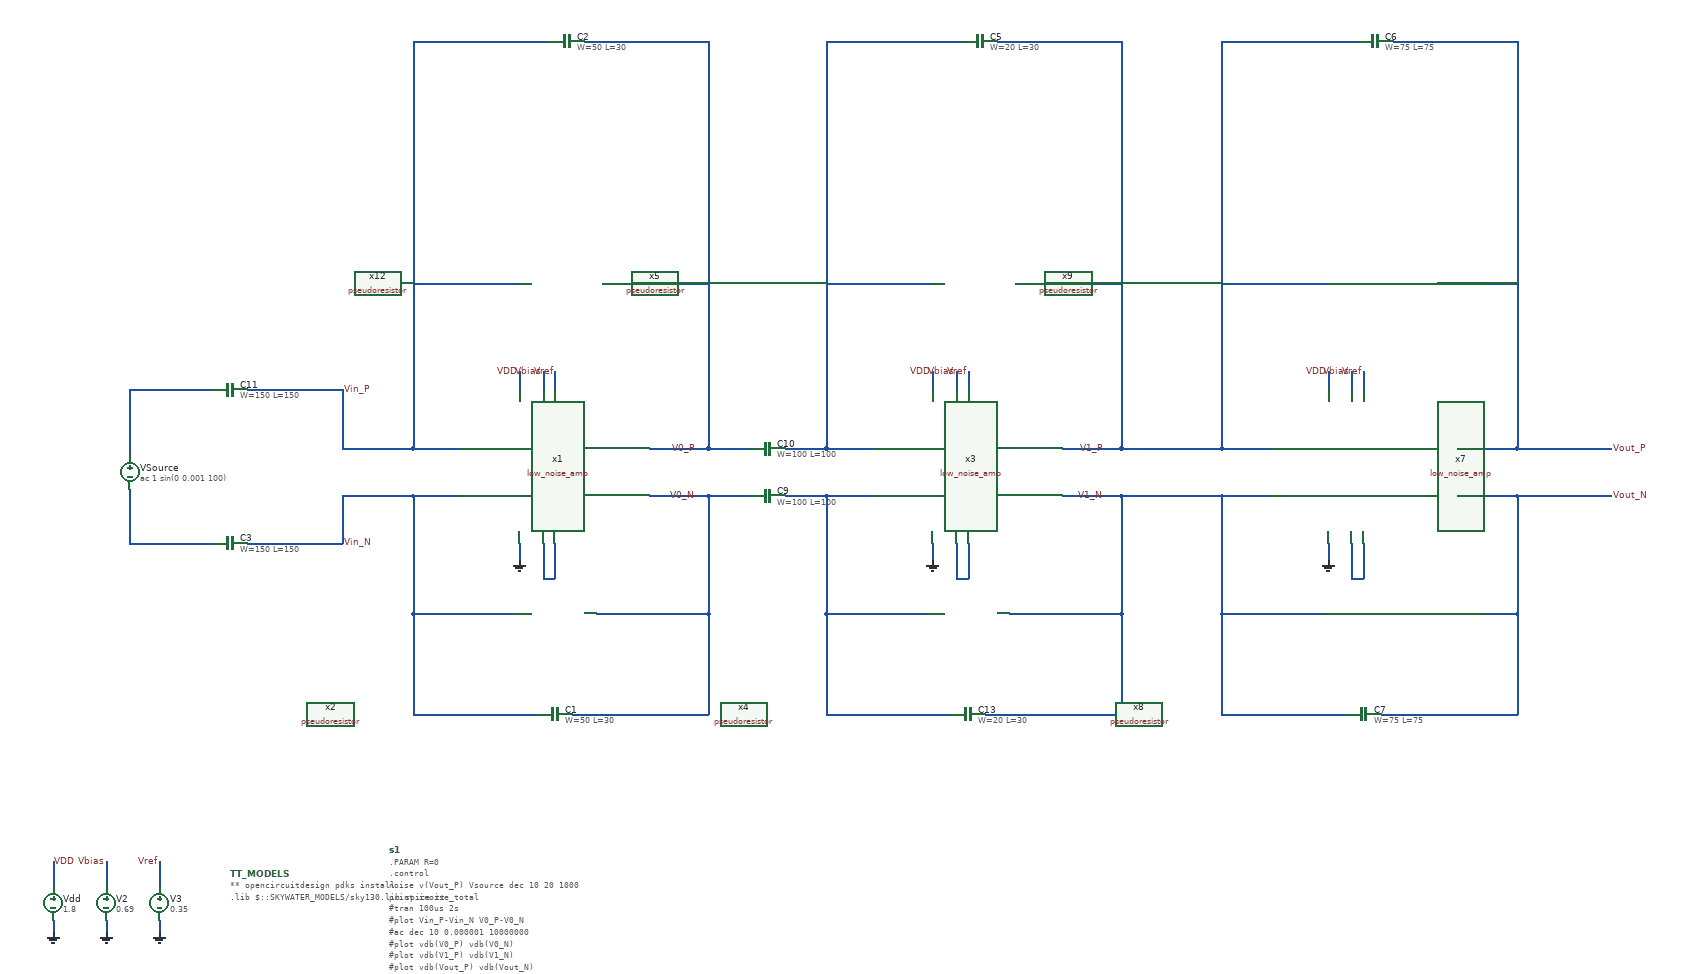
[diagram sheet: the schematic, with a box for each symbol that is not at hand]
v {xschem version=3.4.5 file_version=1.2
}
G {}
K {}
V {}
S {}
E {}
N 710 -910 790 -910 {
lab=Vin_P}
N 1210 -1130 1210 -910 {
lab=V0_P}
N 710 -1130 710 -910 {
lab=Vin_P}
N 710 -830 790 -830 {
lab=Vin_N}
N 1210 -830 1210 -630 {
lab=V0_N}
N 710 -1600 710 -1480 {
lab=Vin_P}
N 710 -1600 940 -1600 {
lab=Vin_P}
N 1210 -1600 1210 -1480 {
lab=V0_P}
N 710 -830 710 -630 {
lab=Vin_N}
N 710 -630 880 -630 {
lab=Vin_N}
N 590 -1010 590 -910 {
lab=Vin_P}
N 590 -830 590 -750 {
lab=Vin_N}
N 930 -750 930 -690 {
lab=#net1}
N 930 -690 950 -690 {
lab=#net1}
N 950 -750 950 -690 {
lab=#net1}
N 890 -1040 890 -1010 {
lab=VDD}
N 930 -1040 930 -1010 {
lab=Vbias}
N 950 -1040 950 -1010 {
lab=Vref}
N 890 -750 890 -720 {
lab=GND}
N 100 -110 100 -90 {
lab=GND}
N 100 -210 100 -170 {
lab=VDD}
N 1020 -630 1210 -630 {
lab=V0_N}
N 230 -1010 230 -900 {
lab=#net2}
N 230 -840 230 -750 {
lab=#net3}
N 1000 -1600 1210 -1600 {
lab=V0_P}
N 190 -110 190 -90 {
lab=GND}
N 190 -210 190 -170 {
lab=Vbias}
N 280 -210 280 -170 {
lab=Vref}
N 280 -110 280 -90 {
lab=GND}
N 1110 -910 1210 -910 {
lab=V0_P}
N 590 -910 710 -910 {
lab=Vin_P}
N 1110 -830 1210 -830 {
lab=V0_N}
N 590 -830 710 -830 {
lab=Vin_N}
N 710 -460 920 -460 {
lab=Vin_N}
N 980 -460 1210 -460 {
lab=V0_N}
N 710 -1480 710 -1130 {
lab=Vin_P}
N 1210 -1480 1210 -1130 {
lab=V0_P}
N 710 -620 710 -460 {
lab=Vin_N}
N 710 -630 710 -620 {
lab=Vin_N}
N 1210 -630 1210 -460 {
lab=V0_N}
N 1410 -910 1490 -910 {
lab=#net4}
N 1910 -1130 1910 -910 {
lab=V1_P}
N 1410 -1130 1410 -910 {
lab=#net4}
N 1410 -830 1490 -830 {
lab=#net5}
N 1910 -830 1910 -630 {
lab=V1_N}
N 1410 -1600 1410 -1480 {
lab=#net4}
N 1410 -1600 1640 -1600 {
lab=#net4}
N 1910 -1600 1910 -1480 {
lab=V1_P}
N 1410 -830 1410 -630 {
lab=#net5}
N 1410 -630 1580 -630 {
lab=#net5}
N 1630 -750 1630 -690 {
lab=#net6}
N 1630 -690 1650 -690 {
lab=#net6}
N 1650 -750 1650 -690 {
lab=#net6}
N 1590 -1040 1590 -1010 {
lab=VDD}
N 1630 -1040 1630 -1010 {
lab=Vbias}
N 1650 -1040 1650 -1010 {
lab=Vref}
N 1590 -750 1590 -720 {
lab=GND}
N 1720 -630 1910 -630 {
lab=V1_N}
N 1700 -1600 1910 -1600 {
lab=V1_P}
N 1810 -910 1910 -910 {
lab=V1_P}
N 1810 -830 1910 -830 {
lab=V1_N}
N 1410 -460 1620 -460 {
lab=#net5}
N 1680 -460 1910 -460 {
lab=V1_N}
N 1410 -1480 1410 -1130 {
lab=#net4}
N 1910 -1480 1910 -1130 {
lab=V1_P}
N 1410 -1190 1590 -1190 {
lab=#net4}
N 1730 -1190 1910 -1190 {
lab=V1_P}
N 1410 -620 1410 -460 {
lab=#net5}
N 1410 -630 1410 -620 {
lab=#net5}
N 1910 -630 1910 -460 {
lab=V1_N}
N 2080 -910 2160 -910 {
lab=#net7}
N 2580 -1130 2580 -910 {
lab=Vout_P}
N 2080 -1130 2080 -910 {
lab=#net7}
N 2080 -830 2160 -830 {
lab=#net8}
N 2580 -830 2580 -630 {
lab=Vout_N}
N 2080 -1600 2080 -1480 {
lab=#net7}
N 2080 -1600 2310 -1600 {
lab=#net7}
N 2580 -1600 2580 -1480 {
lab=Vout_P}
N 2080 -830 2080 -630 {
lab=#net8}
N 2080 -630 2250 -630 {
lab=#net8}
N 2300 -750 2300 -690 {
lab=#net9}
N 2300 -690 2320 -690 {
lab=#net9}
N 2320 -750 2320 -690 {
lab=#net9}
N 2260 -1040 2260 -1010 {
lab=VDD}
N 2300 -1040 2300 -1010 {
lab=Vbias}
N 2320 -1040 2320 -1010 {
lab=Vref}
N 2260 -750 2260 -720 {
lab=GND}
N 2390 -630 2580 -630 {
lab=Vout_N}
N 2370 -1600 2580 -1600 {
lab=Vout_P}
N 2480 -910 2580 -910 {
lab=Vout_P}
N 2480 -830 2580 -830 {
lab=Vout_N}
N 2080 -460 2290 -460 {
lab=#net8}
N 2350 -460 2580 -460 {
lab=Vout_N}
N 2080 -1480 2080 -1130 {
lab=#net7}
N 2580 -1480 2580 -1130 {
lab=Vout_P}
N 2080 -1190 2260 -1190 {
lab=#net7}
N 2400 -1190 2580 -1190 {
lab=Vout_P}
N 2080 -620 2080 -460 {
lab=#net8}
N 2080 -630 2080 -620 {
lab=#net8}
N 2580 -630 2580 -460 {
lab=Vout_N}
N 2580 -830 2740 -830 {
lab=Vout_N}
N 2580 -910 2740 -910 {
lab=Vout_P}
N 710 -1190 890 -1190 {
lab=Vin_P}
N 1030 -1190 1210 -1190 {
lab=V0_P}
N 1340 -830 1410 -830 {
lab=#net5}
N 1340 -910 1410 -910 {
lab=#net4}
N 1210 -830 1280 -830 {
lab=V0_N}
N 1210 -910 1280 -910 {
lab=V0_P}
N 1910 -910 1960 -910 {
lab=V1_P}
N 1910 -830 1960 -830 {
lab=V1_N}
N 2020 -910 2080 -910 {
lab=#net7}
N 2020 -830 2080 -830 {
lab=#net8}
N 230 -750 270 -750 {
lab=#net3}
N 330 -750 370 -750 {
lab=#net3}
N 230 -1010 260 -1010 {
lab=#net2}
N 320 -1010 370 -1010 {
lab=#net2}
N 430 -1010 590 -1010 {
lab=Vin_P}
N 430 -750 590 -750 {
lab=Vin_N}
N 260 -1010 310 -1010 {
lab=#net2}
N 310 -1010 320 -1010 {
lab=#net2}
N 270 -750 330 -750 {
lab=#net3}
N 1960 -910 2020 -910 {}
N 1960 -830 2020 -830 {}
C {low_noise_amp.sym} 950 -870 0 0 {name=x1}
C {devices/lab_pin.sym} 890 -1040 1 0 {name=p1 sig_type=std_logic lab=VDD}
C {devices/lab_pin.sym} 930 -1040 1 0 {name=p2 sig_type=std_logic lab=Vbias}
C {devices/lab_pin.sym} 950 -1040 1 0 {name=p3 sig_type=std_logic lab=Vref}
C {devices/vsource.sym} 100 -140 0 0 {name=Vdd value=1.8 savecurrent=false}
C {devices/vsource.sym} 190 -140 0 0 {name=V2 value=0.69 savecurrent=false}
C {devices/vsource.sym} 280 -140 0 0 {name=V3 value=0.35 savecurrent=false}
C {devices/gnd.sym} 100 -90 0 0 {name=l1 lab=GND}
C {devices/lab_pin.sym} 100 -210 0 1 {name=p5 sig_type=std_logic lab=VDD}
C {devices/vsource.sym} 230 -870 0 0 {name=VSource value="ac 1 sin(0 0.001 100)" savecurrent=false
#sin(0 0.001 1)
}
C {devices/lab_pin.sym} 590 -1010 0 1 {name=p8 sig_type=std_logic lab=Vin_P}
C {devices/lab_pin.sym} 590 -750 0 1 {name=p9 sig_type=std_logic lab=Vin_N}
C {devices/gnd.sym} 190 -90 0 0 {name=l2 lab=GND}
C {devices/gnd.sym} 280 -90 0 0 {name=l3 lab=GND}
C {devices/lab_pin.sym} 190 -210 1 0 {name=p10 sig_type=std_logic lab=Vbias}
C {devices/lab_pin.sym} 280 -210 1 0 {name=p11 sig_type=std_logic lab=Vref}
C {devices/code.sym} 400 -190 0 0 {name=TT_MODELS
only_toplevel=true
format="tcleval( @value )"
value="
** opencircuitdesign pdks install
.lib $::SKYWATER_MODELS/sky130.lib.spice tt

"
spice_ignore=false}
C {devices/code_shown.sym} 670 -230 0 0 {name=s1 only_toplevel=false value="
.PARAM R=0
.control
noise v(Vout_P) Vsource dec 10 20 1000
print inoise_total
#tran 100us 2s
#plot Vin_P-Vin_N V0_P-V0_N
#ac dec 10 0.000001 10000000
#plot vdb(V0_P) vdb(V0_N)
#plot vdb(V1_P) vdb(V1_N)
#plot vdb(Vout_P) vdb(Vout_N)
#plot vdb(V0_P) vdb(V1_P) vdb(Vout_P)
save all
.endc"}
C {devices/gnd.sym} 890 -720 0 0 {name=l4 lab=GND}
C {/home/lcg3895/CE393/pseudoresistor.sym} 570 -460 0 0 {name=x2}
C {sky130_fd_pr/cap_mim_m3_2.sym} 950 -460 3 1 {name=C1 model=cap_mim_m3_2 W=50 L=30 MF=1 spiceprefix=X}
C {sky130_fd_pr/cap_mim_m3_2.sym} 970 -1600 3 1 {name=C2 model=cap_mim_m3_2 W=50 L=30 MF=1 spiceprefix=X}
C {sky130_fd_pr/cap_mim_m3_2.sym} 400 -750 3 1 {name=C3 model=cap_mim_m3_2 W=150 L=150 MF=1 spiceprefix=X}
C {devices/lab_pin.sym} 2740 -910 0 1 {name=p19 sig_type=std_logic lab=Vout_P}
C {devices/lab_pin.sym} 2740 -830 0 1 {name=p20 sig_type=std_logic lab=Vout_N}
C {low_noise_amp.sym} 1650 -870 0 0 {name=x3}
C {devices/lab_pin.sym} 1590 -1040 1 0 {name=p4 sig_type=std_logic lab=VDD}
C {devices/lab_pin.sym} 1630 -1040 1 0 {name=p6 sig_type=std_logic lab=Vbias}
C {devices/lab_pin.sym} 1650 -1040 1 0 {name=p7 sig_type=std_logic lab=Vref}
C {devices/gnd.sym} 1590 -720 0 0 {name=l5 lab=GND}
C {/home/lcg3895/CE393/pseudoresistor.sym} 1270 -460 0 0 {name=x4}
C {/home/lcg3895/CE393/pseudoresistor.sym} 1280 -1020 0 0 {name=x5}
C {low_noise_amp.sym} 2320 -870 0 0 {name=x7}
C {devices/lab_pin.sym} 2260 -1040 1 0 {name=p12 sig_type=std_logic lab=VDD}
C {devices/lab_pin.sym} 2300 -1040 1 0 {name=p13 sig_type=std_logic lab=Vbias}
C {devices/lab_pin.sym} 2320 -1040 1 0 {name=p14 sig_type=std_logic lab=Vref}
C {devices/gnd.sym} 2260 -720 0 0 {name=l6 lab=GND}
C {/home/lcg3895/CE393/pseudoresistor.sym} 1940 -460 0 0 {name=x8}
C {/home/lcg3895/CE393/pseudoresistor.sym} 1950 -1020 0 0 {name=x9}
C {devices/lab_pin.sym} 1190 -830 3 1 {name=p16 sig_type=std_logic lab=V0_N}
C {devices/lab_pin.sym} 1190 -910 3 1 {name=p17 sig_type=std_logic lab=V0_P}
C {devices/lab_pin.sym} 1880 -830 3 1 {name=p15 sig_type=std_logic lab=V1_N}
C {devices/lab_pin.sym} 1880 -910 3 1 {name=p18 sig_type=std_logic lab=V1_P}
C {/home/lcg3895/CE393/pseudoresistor.sym} 580 -1020 0 0 {name=x12}
C {sky130_fd_pr/cap_mim_m3_2.sym} 1310 -830 3 1 {name=C9 model=cap_mim_m3_2 W=100 L=100 MF=1 spiceprefix=X}
C {sky130_fd_pr/cap_mim_m3_2.sym} 1310 -910 3 1 {name=C10 model=cap_mim_m3_2 W=100 L=100 MF=1 spiceprefix=X}
C {sky130_fd_pr/cap_mim_m3_2.sym} 400 -1010 3 1 {name=C11 model=cap_mim_m3_2 W=150 L=150 MF=1 spiceprefix=X}
C {sky130_fd_pr/cap_mim_m3_2.sym} 1670 -1600 3 1 {name=C5 model=cap_mim_m3_2 W=20 L=30 MF=1 spiceprefix=X}
C {sky130_fd_pr/cap_mim_m3_2.sym} 1650 -460 3 1 {name=C13 model=cap_mim_m3_2 W=20 L=30 MF=1 spiceprefix=X}
C {sky130_fd_pr/cap_mim_m3_2.sym} 2320 -460 3 1 {name=C7 model=cap_mim_m3_2 W=75 L=75 MF=1 spiceprefix=X}
C {sky130_fd_pr/cap_mim_m3_2.sym} 2340 -1600 3 1 {name=C6 model=cap_mim_m3_2 W=75 L=75 MF=1 spiceprefix=X}
